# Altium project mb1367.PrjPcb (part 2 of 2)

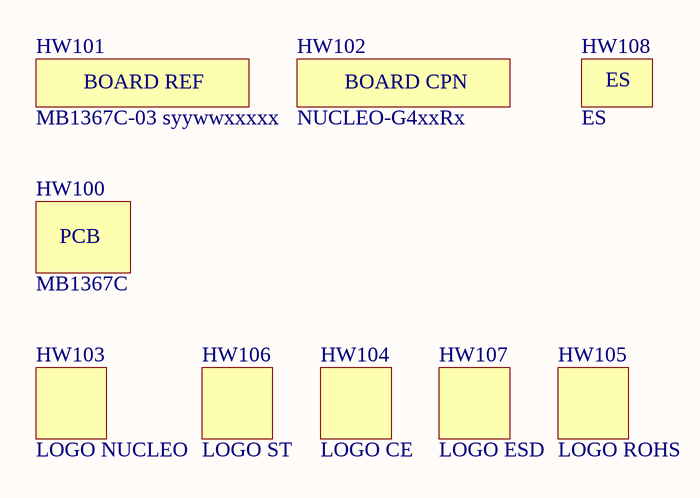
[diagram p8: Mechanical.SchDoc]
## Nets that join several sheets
3V3: Arduino_extension_connectors (CN6.4 CN7.16 R25.1 SB39.1), Power (JP6.1 SB5.2), ST_LINK_V3E (CN4.3 R19.2)
5V: Arduino_extension_connectors (CN6.5 CN7.18), Power (11 pins), ST_LINK_V3E (R12.1)
5V_USB_CHGR: Arduino_extension_connectors (CN10.8), Power (JP5.7), ST_LINK_V3E (8 pins)
5V_USB_STLK: Power (JP5.1), ST_LINK_V3E (C5.2 U4.1)
5V_VIN: Arduino_extension_connectors (R30.2), Power (C38.2 JP5.3 U11.2 U11.4), ST_LINK_V3E (D3.1)
AGND: Arduino_extension_connectors (CN10.32), Power (C46.1 C50.1 R34.1 U14.5), STM32_microcontroller_power (7 pins)
E5V: Arduino_extension_connectors (CN7.6), Power (JP5.5), ST_LINK_V3E (D2.1)
GND: Arduino_extension_connectors (11 pins), Power (10 pins), STM32_microcontroller_IOs (14 pins), STM32_microcontroller_power (11 pins), ST_LINK_V3E (102 pins)
VBAT: Arduino_extension_connectors (CN7.33), STM32_microcontroller_power (C53.2 SB38.2 U13.1)
VDD: Arduino_extension_connectors (CN7.5), Power (JP6.2), STM32_microcontroller_IOs (B1.1 B1.2), STM32_microcontroller_power (13 pins)
VIN: Arduino_extension_connectors (CN6.8 CN7.24), Power (C41.2 U11.3)
VREF: Power (5 pins), STM32_microcontroller_power (JP8.1)
VREFP: Arduino_extension_connectors (CN5.8 CN10.7), STM32_microcontroller_power (5 pins)
ARD_D0_RX: Arduino_extension_connectors (CN9.1 CN10.37), STM32_microcontroller_IOs (SB19.2 SB22.2)
ARD_D1_TX: Arduino_extension_connectors (CN9.2 CN10.35), STM32_microcontroller_IOs (SB13.2 SB18.2)
MCO: STM32_microcontroller_IOs (SB27.1), ST_LINK_V3E (C3.2 R4.2)
PA0: Arduino_extension_connectors (CN7.28 CN8.1), STM32_microcontroller_IOs (SB21.2 U13.12)
PA1: Arduino_extension_connectors (CN7.30 CN8.2), STM32_microcontroller_IOs (U13.13)
PA4: Arduino_extension_connectors (CN7.32 CN8.3), STM32_microcontroller_IOs (U13.18)
PA5: Arduino_extension_connectors (CN5.6 CN10.11 SB6.1), STM32_microcontroller_IOs (U13.19)
PA6: Arduino_extension_connectors (CN5.5 CN10.13), STM32_microcontroller_IOs (U13.20)
PA7: Arduino_extension_connectors (CN5.4 CN10.15), STM32_microcontroller_IOs (U13.21)
PA8: Arduino_extension_connectors (CN9.8 CN10.23), STM32_microcontroller_IOs (U13.42)
PA9: Arduino_extension_connectors (CN5.1 CN10.21), STM32_microcontroller_IOs (U13.43)
PA10: Arduino_extension_connectors (CN9.3 CN10.33), STM32_microcontroller_IOs (U13.44)
PA11: Arduino_extension_connectors (CN10.14), STM32_microcontroller_IOs (U13.45)
PA12: Arduino_extension_connectors (CN10.12), STM32_microcontroller_IOs (U13.46)
PA13: Arduino_extension_connectors (CN7.13), STM32_microcontroller_IOs (SB40.2 U13.49)
PA14: Arduino_extension_connectors (CN7.15), STM32_microcontroller_IOs (SB41.2 U13.50)
PA15: Arduino_extension_connectors (SB7.1 SB37.2), STM32_microcontroller_IOs (R32.2 U13.51)
PB0: Arduino_extension_connectors (CN7.34 CN8.4), STM32_microcontroller_IOs (U13.24)
PB1: Arduino_extension_connectors (CN10.24), STM32_microcontroller_IOs (U13.25)
PB2: Arduino_extension_connectors (CN10.22), STM32_microcontroller_IOs (U13.26)
PB3: Arduino_extension_connectors (CN9.4 CN10.31), STM32_microcontroller_IOs (SB15.1 U13.56)
PB4: Arduino_extension_connectors (CN9.6 CN10.27), STM32_microcontroller_IOs (U13.57)
PB5: Arduino_extension_connectors (CN9.5 CN10.29), STM32_microcontroller_IOs (U13.58)
PB6: Arduino_extension_connectors (CN5.3 CN10.17), STM32_microcontroller_IOs (U13.59)
PB7: Arduino_extension_connectors (CN7.21), STM32_microcontroller_IOs (U13.60)
PB8: Arduino_extension_connectors (SB2.2 SB4.1), STM32_microcontroller_IOs (JP7.1 U13.61)
PB9: Arduino_extension_connectors (CN5.9 CN10.5 SB34.2), STM32_microcontroller_IOs (U13.62)
PB10: Arduino_extension_connectors (CN9.7 CN10.25), STM32_microcontroller_IOs (U13.30)
PB11: Arduino_extension_connectors (CN10.18), STM32_microcontroller_IOs (U13.33)
PB12: Arduino_extension_connectors (CN10.16), STM32_microcontroller_IOs (U13.34)
PB13: Arduino_extension_connectors (CN10.30), STM32_microcontroller_IOs (U13.35)
PB14: Arduino_extension_connectors (CN10.28), STM32_microcontroller_IOs (U13.36)
PB15: Arduino_extension_connectors (CN10.26), STM32_microcontroller_IOs (U13.37)
PC0: Arduino_extension_connectors (SB36.1), STM32_microcontroller_IOs (U13.8)
PC1: Arduino_extension_connectors (SB35.1), STM32_microcontroller_IOs (U13.9)
PC2: Arduino_extension_connectors (CN7.35), STM32_microcontroller_IOs (U13.10)
PC3: Arduino_extension_connectors (CN7.37), STM32_microcontroller_IOs (U13.11)
PC4: Arduino_extension_connectors (SB33.2), STM32_microcontroller_IOs (SB12.2 SB13.1 U13.22)
PC5: Arduino_extension_connectors (SB3.2), STM32_microcontroller_IOs (SB19.1 SB20.2 U13.23)
PC6: Arduino_extension_connectors (CN10.4), STM32_microcontroller_IOs (U13.38)
PC7: Arduino_extension_connectors (CN5.2 CN10.19), STM32_microcontroller_IOs (U13.39)
PC8: Arduino_extension_connectors (CN10.2), STM32_microcontroller_IOs (U13.40)
PC9: Arduino_extension_connectors (CN10.1), STM32_microcontroller_IOs (U13.41)
PC10: Arduino_extension_connectors (CN7.1), STM32_microcontroller_IOs (U13.52)
PC11: Arduino_extension_connectors (CN7.2), STM32_microcontroller_IOs (U13.53)
PC12: Arduino_extension_connectors (CN7.3), STM32_microcontroller_IOs (U13.54)
PC13: Arduino_extension_connectors (CN7.23), STM32_microcontroller_IOs (SB16.2 U13.2)
PC14: Arduino_extension_connectors (CN7.25), STM32_microcontroller_IOs (SB32.1)
PC15: Arduino_extension_connectors (CN7.27), STM32_microcontroller_IOs (SB29.1)
PD2: Arduino_extension_connectors (CN7.4), STM32_microcontroller_IOs (U13.55)
PF0: Arduino_extension_connectors (CN7.29), STM32_microcontroller_IOs (SB28.1)
PF1: Arduino_extension_connectors (CN7.31), STM32_microcontroller_IOs (SB24.1)
T_JTDI: STM32_microcontroller_IOs (SB9.1), ST_LINK_V3E (CN4.10 U6.1)
T_NRST: Arduino_extension_connectors (CN6.3 CN7.14), STM32_microcontroller_IOs (5 pins), ST_LINK_V3E (CN4.12 R18.2 U8.1)
T_SWCLK: STM32_microcontroller_IOs (SB41.1), ST_LINK_V3E (CN4.6 R10.2 U6.4)
T_SWDIO: STM32_microcontroller_IOs (SB40.1), ST_LINK_V3E (CN4.4 R9.2 U6.5)
T_SWO: STM32_microcontroller_IOs (SB15.2), ST_LINK_V3E (CN4.8 R13.2 U6.3)
T_VCP_RX: STM32_microcontroller_IOs (SB20.1 SB23.1), ST_LINK_V3E (CN4.13 R22.2 U1.1)
T_VCP_TX: STM32_microcontroller_IOs (SB12.1 SB17.1), ST_LINK_V3E (CN4.14 R23.2 U1.3)

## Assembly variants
G474RE: not fitted C3 CN2 HW1 HW20 R6 SB8 SB10 SB12 SB14 SB18 SB20 SB21 SB22 SB24 SB27 SB28 SB29 SB32 SB34 SB37
G431RB: not fitted C3 CN2 HW1 HW20 R6 SB8 SB10 SB12 SB14 SB18 SB20 SB21 SB22 SB24 SB27 SB28 SB29 SB32 SB34 SB37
